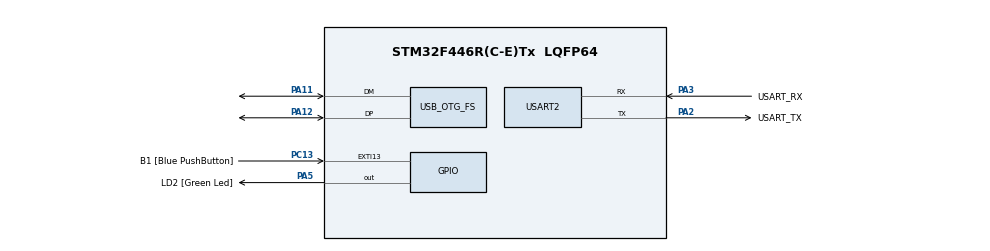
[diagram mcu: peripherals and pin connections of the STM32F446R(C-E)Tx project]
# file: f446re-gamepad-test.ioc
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Mcu.Family=STM32F4
Mcu.Name=STM32F446R(C-E)Tx
Mcu.Package=LQFP64
NVIC.OTG_FS_IRQn=true\:0\:0\:false\:false\:true\:false
NVIC.PriorityGroup=NVIC_PRIORITYGROUP_0
PA11.Mode=Host_Only
PA11.Signal=USB_OTG_FS_DM
PA12.Mode=Host_Only
PA12.Signal=USB_OTG_FS_DP
PA13.GPIO_Label=TMS
PA13.Mode=Serial_Wire
PA13.Signal=SYS_JTMS-SWDIO
PA14.GPIO_Label=TCK
PA14.Mode=Serial_Wire
PA14.Signal=SYS_JTCK-SWCLK
PA2.GPIO_Label=USART_TX
PA2.Mode=Asynchronous
PA2.Signal=USART2_TX
PA3.GPIO_Label=USART_RX
PA3.Mode=Asynchronous
PA3.Signal=USART2_RX
PA5.GPIO_Label=LD2 [Green Led]
PA5.Signal=GPIO_Output
PB3.GPIO_Label=SWO
PB3.Signal=SYS_JTDO-SWO
PC13.GPIO_Label=B1 [Blue PushButton]
PC13.GPIO_ModeDefaultEXTI=GPIO_MODE_IT_FALLING
PC13.Signal=GPXTI13
PC14-OSC32_IN.Mode=LSE-External-Oscillator
PC14-OSC32_IN.Signal=RCC_OSC32_IN
PC15-OSC32_OUT.Mode=LSE-External-Oscillator
PC15-OSC32_OUT.Signal=RCC_OSC32_OUT
PH0-OSC_IN.Mode=HSE-External-Oscillator
PH0-OSC_IN.Signal=RCC_OSC_IN
PH1-OSC_OUT.Mode=HSE-External-Oscillator
PH1-OSC_OUT.Signal=RCC_OSC_OUT
ProjectManager.HeapSize=0x200
ProjectManager.StackSize=0x400
ProjectManager.TargetToolchain=Other Toolchains (GPDSC)
RCC.48MHZClocksFreq_Value=84000000
RCC.AHBFreq_Value=72000000
RCC.APB1CLKDivider=RCC_HCLK_DIV2
RCC.APB1Freq_Value=36000000
RCC.APB1TimFreq_Value=72000000
RCC.APB2Freq_Value=72000000
RCC.APB2TimFreq_Value=72000000
RCC.CortexFreq_Value=72000000
RCC.FLatency-AdvancedSettings=FLASH_LATENCY_2
RCC.HCLKFreq_Value=72000000
RCC.HSE_VALUE=8000000
RCC.HSI_VALUE=16000000
RCC.PLLM=4
RCC.PLLN=72
RCC.PLLQ=3
RCC.SYSCLKFreq_VALUE=72000000
RCC.SYSCLKSource=RCC_SYSCLKSOURCE_PLLCLK
RCC.USBFreq_Value=48000000
RCC.VCOOutputFreq_Value=144000000
USART2.VirtualMode=VM_ASYNC
USB_HOST.USBH_HandleTypeDef-HID_FS=hUsbHostFS
USB_HOST.VirtualModeFS=Hid
USB_OTG_FS.VirtualMode=Host_Only
USB_OTG_FS.phy_itface=HCD_PHY_EMBEDDED
VP_USB_HOST_VS_USB_HOST_HID_FS.Mode=HID_FS
board=NUCLEO-F446RE

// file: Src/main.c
/**
  ******************************************************************************
  * @file           : main.c
  * @brief          : Main program body
  ******************************************************************************
  * This notice applies to any and all portions of this file
  * that are not between comment pairs USER CODE BEGIN and
  * USER CODE END. Other portions of this file, whether
  * inserted by the user or by software development tools
  * are owned by their respective copyright owners.
  *
  * Copyright (c) 2018 STMicroelectronics International N.V.
  * All rights reserved.
  *
  * Redistribution and use in source and binary forms, with or without
  * modification, are permitted, provided that the following conditions are met:
  *
  * 1. Redistribution of source code must retain the above copyright notice,
  *    this list of conditions and the following disclaimer.
  * 2. Redistributions in binary form must reproduce the above copyright notice,
  *    this list of conditions and the following disclaimer in the documentation
  *    and/or other materials provided with the distribution.
  * 3. Neither the name of STMicroelectronics nor the names of other
  *    contributors to this software may be used to endorse or promote products
  *    derived from this software without specific written permission.
  * 4. This software, including modifications and/or derivative works of this
  *    software, must execute solely and exclusively on microcontroller or
  *    microprocessor devices manufactured by or for STMicroelectronics.
  * 5. Redistribution and use of this software other than as permitted under
  *    this license is void and will automatically terminate your rights under
  *    this license.
  *
  * THIS SOFTWARE IS PROVIDED BY STMICROELECTRONICS AND CONTRIBUTORS "AS IS"
  * AND ANY EXPRESS, IMPLIED OR STATUTORY WARRANTIES, INCLUDING, BUT NOT
  * LIMITED TO, THE IMPLIED WARRANTIES OF MERCHANTABILITY, FITNESS FOR A
  * PARTICULAR PURPOSE AND NON-INFRINGEMENT OF THIRD PARTY INTELLECTUAL PROPERTY
  * RIGHTS ARE DISCLAIMED TO THE FULLEST EXTENT PERMITTED BY LAW. IN NO EVENT
  * SHALL STMICROELECTRONICS OR CONTRIBUTORS BE LIABLE FOR ANY DIRECT, INDIRECT,
  * INCIDENTAL, SPECIAL, EXEMPLARY, OR CONSEQUENTIAL DAMAGES (INCLUDING, BUT NOT
  * LIMITED TO, PROCUREMENT OF SUBSTITUTE GOODS OR SERVICES; LOSS OF USE, DATA,
  * OR PROFITS; OR BUSINESS INTERRUPTION) HOWEVER CAUSED AND ON ANY THEORY OF
  * LIABILITY, WHETHER IN CONTRACT, STRICT LIABILITY, OR TORT (INCLUDING
  * NEGLIGENCE OR OTHERWISE) ARISING IN ANY WAY OUT OF THE USE OF THIS SOFTWARE,
  * EVEN IF ADVISED OF THE POSSIBILITY OF SUCH DAMAGE.
  *
  ******************************************************************************
  */
#include "main.h"
#include "stm32f4xx_hal.h"
#include "usart.h"
#include "usb_host.h"
#include "gpio.h"

/* USER CODE BEGIN Includes */
#include "user_main.h"

/* USER CODE END Includes */

/* USER CODE BEGIN PV */
/* Private variables ---------------------------------------------------------*/

/* USER CODE END PV */

void SystemClock_Config(void);
void MX_USB_HOST_Process(void);

/* USER CODE BEGIN PFP */
/* Private function prototypes -----------------------------------------------*/

/* USER CODE END PFP */

int main(void)
{

  /* MCU Configuration----------------------------------------------------------*/

  /* Reset of all peripherals, Initializes the Flash interface and the Systick. */
  HAL_Init();

  /* Configure the system clock */
  SystemClock_Config();

  /* Initialize all configured peripherals */
  MX_GPIO_Init();
  MX_USART2_UART_Init();
  MX_USB_HOST_Init();
  /* USER CODE BEGIN 2 */
  userInit();

  /* USER CODE END 2 */

  /* Infinite loop */
  /* USER CODE BEGIN WHILE */
  while (1)
  {
    userMain();

  /* USER CODE END WHILE */
    MX_USB_HOST_Process();

  }

}

void SystemClock_Config(void)
{

  RCC_OscInitTypeDef RCC_OscInitStruct;
  RCC_ClkInitTypeDef RCC_ClkInitStruct;
  RCC_PeriphCLKInitTypeDef PeriphClkInitStruct;

    /**Configure the main internal regulator output voltage
    */
  __HAL_RCC_PWR_CLK_ENABLE();

  __HAL_PWR_VOLTAGESCALING_CONFIG(PWR_REGULATOR_VOLTAGE_SCALE1);

    /**Initializes the CPU, AHB and APB busses clocks
    */
  RCC_OscInitStruct.OscillatorType = RCC_OSCILLATORTYPE_HSE;
  RCC_OscInitStruct.HSEState = RCC_HSE_BYPASS;
  RCC_OscInitStruct.PLL.PLLState = RCC_PLL_ON;
  RCC_OscInitStruct.PLL.PLLSource = RCC_PLLSOURCE_HSE;
  RCC_OscInitStruct.PLL.PLLM = 4;
  RCC_OscInitStruct.PLL.PLLN = 180;
  RCC_OscInitStruct.PLL.PLLP = RCC_PLLP_DIV2;
  RCC_OscInitStruct.PLL.PLLQ = 3;
  RCC_OscInitStruct.PLL.PLLR = 2;
  if (HAL_RCC_OscConfig(&RCC_OscInitStruct) != HAL_OK)
  {
    _Error_Handler(__FILE__, __LINE__);
  }

    /**Activate the Over-Drive mode
    */
  if (HAL_PWREx_EnableOverDrive() != HAL_OK)
  {
    _Error_Handler(__FILE__, __LINE__);
  }

    /**Initializes the CPU, AHB and APB busses clocks
    */
  RCC_ClkInitStruct.ClockType = RCC_CLOCKTYPE_HCLK|RCC_CLOCKTYPE_SYSCLK
                              |RCC_CLOCKTYPE_PCLK1|RCC_CLOCKTYPE_PCLK2;
  RCC_ClkInitStruct.SYSCLKSource = RCC_SYSCLKSOURCE_PLLCLK;
  RCC_ClkInitStruct.AHBCLKDivider = RCC_SYSCLK_DIV1;
  RCC_ClkInitStruct.APB1CLKDivider = RCC_HCLK_DIV4;
  RCC_ClkInitStruct.APB2CLKDivider = RCC_HCLK_DIV4;

  if (HAL_RCC_ClockConfig(&RCC_ClkInitStruct, FLASH_LATENCY_5) != HAL_OK)
  {
    _Error_Handler(__FILE__, __LINE__);
  }

  PeriphClkInitStruct.PeriphClockSelection = RCC_PERIPHCLK_CLK48;
  PeriphClkInitStruct.PLLSAI.PLLSAIM = 4;
  PeriphClkInitStruct.PLLSAI.PLLSAIN = 96;
  PeriphClkInitStruct.PLLSAI.PLLSAIQ = 2;
  PeriphClkInitStruct.PLLSAI.PLLSAIP = RCC_PLLSAIP_DIV4;
  PeriphClkInitStruct.PLLSAIDivQ = 1;
  PeriphClkInitStruct.Clk48ClockSelection = RCC_CLK48CLKSOURCE_PLLSAIP;
  if (HAL_RCCEx_PeriphCLKConfig(&PeriphClkInitStruct) != HAL_OK)
  {
    _Error_Handler(__FILE__, __LINE__);
  }

    /**Configure the Systick interrupt time
    */
  HAL_SYSTICK_Config(HAL_RCC_GetHCLKFreq()/1000);

    /**Configure the Systick
    */
  HAL_SYSTICK_CLKSourceConfig(SYSTICK_CLKSOURCE_HCLK);

  /* SysTick_IRQn interrupt configuration */
  HAL_NVIC_SetPriority(SysTick_IRQn, 0, 0);
}

void _Error_Handler(char *file, int line)
{
  while(1)
  {
  }
}

/************************ (C) COPYRIGHT STMicroelectronics *****END OF FILE****/
